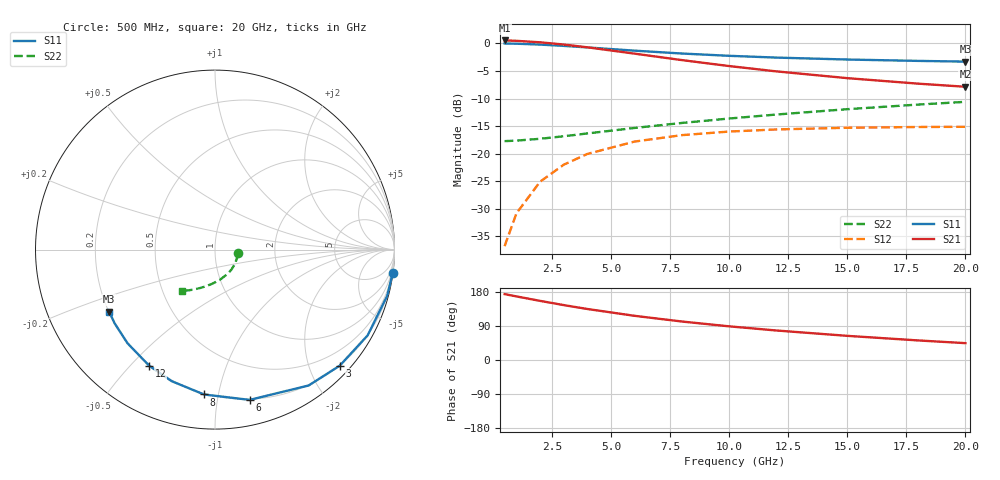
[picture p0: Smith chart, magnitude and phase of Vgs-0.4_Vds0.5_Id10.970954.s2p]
# Hz S RI R 50
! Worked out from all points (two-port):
!   12 points, 500 MHz to 20 GHz, reference 50 ohm
!   highest |S21| = 0.53 dB at 500 MHz (marker M1); lowest = -7.9 dB at 20 GHz (marker M2)
!   |S21| within 3 dB of the highest: start of sweep to 7.041 GHz
!   lowest |S11| = -3.3 dB at 20 GHz (marker M3), VSWR 5.32, Z = 10.1 - j13 ohm
!   |S11| at or under -10 dB: nowhere
!   |S22| runs from -17.7 to -10.6 dB; largest |S21 - S12| = 1.1
!   S11 on the Smith chart (normalised r, x): 500 MHz: 0, -15; 3 GHz: 0.19, -2.53; 6 GHz: 0.19, -1.24; 8 GHz: 0.19, -0.91; 12 GHz: 0.20, -0.57; 20 GHz: 0.20, -0.26
5e8  0.9898 -0.1301  -1.057 0.1132  0.00124 0.0145  0.1283 -0.0209
1e9  0.9601 -0.2557  -1.031 0.2224  0.00489 0.0284  0.1247 -0.0413
2e9  0.8503 -0.4782  -0.9349 0.4156  0.0183 0.0526  0.1114 -0.0789
3e9  0.6951 -0.6467  -0.7991 0.5613  0.0372 0.0702  0.0923 -0.1104
4e9  0.5213 -0.7572  -0.6471 0.6561  0.0583 0.0805  0.0702 -0.1355
6e9  0.1933 -0.8373  -0.3613 0.722  0.0977 0.084  0.0259 -0.1692
8e9  -0.061 -0.8072  -0.1413 0.6914  0.1274 0.0739  -0.0135 -0.1895
1e10  -0.2414 -0.7329  0.0125 0.6229  0.1475 0.0587  -0.0476 -0.2028
1.2e10  -0.3666 -0.6469  0.1172 0.5452  0.1604 0.0424  -0.078 -0.2126
1.5e10  -0.4874 -0.5218  0.2143 0.4341  0.1708 0.0192  -0.1201 -0.223
1.8e10  -0.5592 -0.4109  0.2677 0.3384  0.1746 -0.00133  -0.1599 -0.2285
2e10  -0.5902 -0.3451  0.2886 0.2833  0.1749 -0.0135  -0.1856 -0.2295
